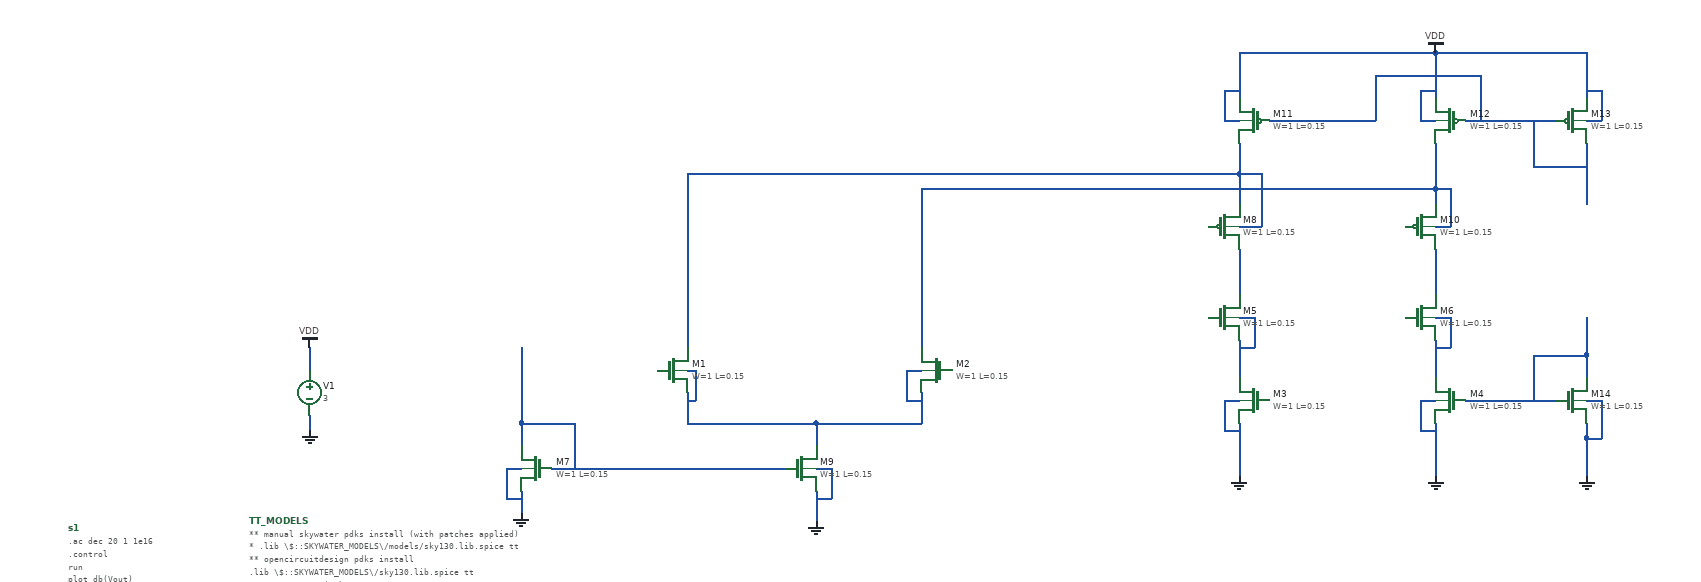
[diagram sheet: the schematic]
v {xschem version=2.9.9 file_version=1.2 }
G {}
K {}
V {}
S {}
E {}
N 1510 -730 1510 -710 { lab=GND}
N 1510 -820 1510 -790 { lab=VDD}
N 2180 -630 2180 -590 { lab=GND}
N 2010 -760 2010 -720 { lab=#net1}
N 2010 -720 2180 -720 { lab=#net1}
N 2180 -720 2180 -690 { lab=#net1}
N 2180 -720 2320 -720 { lab=#net1}
N 2320 -760 2320 -720 { lab=#net1}
N 2740 -720 2740 -650 { lab=GND}
N 3000 -720 3000 -690 { lab=GND}
N 3000 -690 3000 -650 { lab=GND}
N 2180 -660 2200 -660 { lab=GND}
N 2200 -660 2200 -620 { lab=GND}
N 2180 -620 2200 -620 { lab=GND}
N 2300 -790 2320 -790 { lab=#net1}
N 2300 -790 2300 -750 { lab=#net1}
N 2300 -750 2320 -750 { lab=#net1}
N 2010 -790 2020 -790 { lab=#net1}
N 2020 -790 2020 -750 { lab=#net1}
N 2010 -750 2020 -750 { lab=#net1}
N 2720 -750 2740 -750 { lab=GND}
N 2720 -750 2720 -710 { lab=GND}
N 2720 -710 2740 -710 { lab=GND}
N 2980 -750 3000 -750 { lab=GND}
N 2980 -750 2980 -710 { lab=GND}
N 2980 -710 3000 -710 { lab=GND}
N 2740 -830 2740 -780 { lab=#net2}
N 3000 -830 3000 -780 { lab=#net3}
N 2740 -860 2760 -860 { lab=#net2}
N 2760 -860 2760 -820 { lab=#net2}
N 2740 -820 2760 -820 { lab=#net2}
N 3000 -860 3020 -860 { lab=#net3}
N 3020 -860 3020 -820 { lab=#net3}
N 3000 -820 3020 -820 { lab=#net3}
N 2740 -980 2760 -980 { lab=#net4}
N 2740 -1090 2740 -1050 { lab=#net4}
N 3000 -980 3020 -980 { lab=#net5}
N 3020 -1030 3020 -980 { lab=#net5}
N 3000 -1030 3020 -1030 { lab=#net5}
N 3000 -1030 3000 -1010 { lab=#net5}
N 2740 -1210 2740 -1150 { lab=#net6}
N 2740 -1210 3000 -1210 { lab=#net6}
N 3000 -1210 3000 -1150 { lab=#net6}
N 2980 -1120 3000 -1120 { lab=#net6}
N 2980 -1160 2980 -1120 { lab=#net6}
N 2980 -1160 3000 -1160 { lab=#net6}
N 2720 -1120 2740 -1120 { lab=#net6}
N 2720 -1160 2720 -1120 { lab=#net6}
N 2720 -1160 2740 -1160 { lab=#net6}
N 2010 -1050 2010 -820 { lab=#net4}
N 2010 -1050 2740 -1050 { lab=#net4}
N 2760 -980 2770 -980 { lab=#net4}
N 2770 -1040 2770 -980 { lab=#net4}
N 2740 -950 2740 -890 { lab=#net7}
N 3000 -950 3000 -890 { lab=#net8}
N 2770 -1050 2770 -1040 { lab=#net4}
N 2740 -1050 2770 -1050 { lab=#net4}
N 2740 -1050 2740 -1010 { lab=#net4}
N 3000 -1090 3000 -1030 { lab=#net5}
N 2320 -1030 3000 -1030 { lab=#net5}
N 2320 -1030 2320 -820 { lab=#net5}
N 3000 -1210 3200 -1210 { lab=#net6}
N 3200 -1210 3200 -1150 { lab=#net6}
N 3200 -1120 3220 -1120 { lab=#net6}
N 3220 -1160 3220 -1120 { lab=#net6}
N 3200 -1160 3220 -1160 { lab=#net6}
N 3200 -1090 3200 -1010 { lab=#net9}
N 3040 -1120 3160 -1120 { lab=#net9}
N 2780 -1120 2920 -1120 { lab=#net9}
N 2920 -1180 2920 -1120 { lab=#net9}
N 2920 -1180 3060 -1180 { lab=#net9}
N 3060 -1180 3060 -1120 { lab=#net9}
N 3200 -750 3220 -750 { lab=GND}
N 3220 -750 3220 -700 { lab=GND}
N 3200 -700 3220 -700 { lab=GND}
N 3200 -720 3200 -700 { lab=GND}
N 3200 -700 3200 -650 { lab=GND}
N 3040 -750 3160 -750 { lab=#net10}
N 3130 -810 3130 -750 { lab=#net10}
N 3130 -810 3200 -810 { lab=#net10}
N 3200 -810 3200 -780 { lab=#net10}
N 3130 -1120 3130 -1060 { lab=#net9}
N 3130 -1060 3200 -1060 { lab=#net9}
N 3200 -860 3200 -810 { lab=#net10}
N 1790 -630 1790 -600 { lab=GND}
N 1770 -660 1790 -660 { lab=GND}
N 1770 -660 1770 -620 { lab=GND}
N 1770 -620 1790 -620 { lab=GND}
N 1830 -660 2140 -660 { lab=#net11}
N 1860 -720 1860 -660 { lab=#net11}
N 1790 -720 1860 -720 { lab=#net11}
N 1790 -720 1790 -690 { lab=#net11}
N 1790 -820 1790 -720 { lab=#net11}
C {devices/code.sym} 1430 -590 0 0 {name=TT_MODELS
only_toplevel=true
format="tcleval( @value )"
value="** manual skywater pdks install (with patches applied)
* .lib \\\\$::SKYWATER_MODELS\\\\/models/sky130.lib.spice tt

** opencircuitdesign pdks install
.lib \\\\$::SKYWATER_MODELS\\\\/sky130.lib.spice tt

.param mc_mm_switch=0
.param mc_pr_switch=0
"}
C {devices/code_shown.sym} 1190 -580 0 0 {name=s1 only_toplevel=false value=".ac dec 20 1 1e16
.control
run
plot db(Vout)
.endc
.save all"}
C {devices/vsource.sym} 1510 -760 0 0 {name=V1 value=3}
C {devices/gnd.sym} 1510 -710 0 0 {name=l1 lab=GND}
C {devices/vdd.sym} 1510 -820 0 0 {name=l11 lab=VDD}
C {sky130_fd_pr/nfet_01v8.sym} 2160 -660 0 0 {name=M9
L=0.15
W=1
nf=1 
mult=1
ad="'int((nf+1)/2) * W/nf * 0.29'" 
pd="'2*int((nf+1)/2) * (W/nf + 0.29)'"
as="'int((nf+2)/2) * W/nf * 0.29'" 
ps="'2*int((nf+2)/2) * (W/nf + 0.29)'"
nrd="'0.29 / W'" nrs="'0.29 / W'"
sa=0 sb=0 sd=0
model=nfet_01v8
spiceprefix=X
}
C {devices/gnd.sym} 2180 -590 0 0 {name=l2 lab=GND}
C {sky130_fd_pr/nfet_01v8.sym} 1990 -790 0 0 {name=M1
L=0.15
W=1
nf=1 
mult=1
ad="'int((nf+1)/2) * W/nf * 0.29'" 
pd="'2*int((nf+1)/2) * (W/nf + 0.29)'"
as="'int((nf+2)/2) * W/nf * 0.29'" 
ps="'2*int((nf+2)/2) * (W/nf + 0.29)'"
nrd="'0.29 / W'" nrs="'0.29 / W'"
sa=0 sb=0 sd=0
model=nfet_01v8
spiceprefix=X
}
C {sky130_fd_pr/nfet_01v8.sym} 2340 -790 0 1 {name=M2
L=0.15
W=1
nf=1 
mult=1
ad="'int((nf+1)/2) * W/nf * 0.29'" 
pd="'2*int((nf+1)/2) * (W/nf + 0.29)'"
as="'int((nf+2)/2) * W/nf * 0.29'" 
ps="'2*int((nf+2)/2) * (W/nf + 0.29)'"
nrd="'0.29 / W'" nrs="'0.29 / W'"
sa=0 sb=0 sd=0
model=nfet_01v8
spiceprefix=X
}
C {sky130_fd_pr/nfet_01v8.sym} 2760 -750 0 1 {name=M3
L=0.15
W=1
nf=1 
mult=1
ad="'int((nf+1)/2) * W/nf * 0.29'" 
pd="'2*int((nf+1)/2) * (W/nf + 0.29)'"
as="'int((nf+2)/2) * W/nf * 0.29'" 
ps="'2*int((nf+2)/2) * (W/nf + 0.29)'"
nrd="'0.29 / W'" nrs="'0.29 / W'"
sa=0 sb=0 sd=0
model=nfet_01v8
spiceprefix=X
}
C {sky130_fd_pr/nfet_01v8.sym} 3020 -750 0 1 {name=M4
L=0.15
W=1
nf=1 
mult=1
ad="'int((nf+1)/2) * W/nf * 0.29'" 
pd="'2*int((nf+1)/2) * (W/nf + 0.29)'"
as="'int((nf+2)/2) * W/nf * 0.29'" 
ps="'2*int((nf+2)/2) * (W/nf + 0.29)'"
nrd="'0.29 / W'" nrs="'0.29 / W'"
sa=0 sb=0 sd=0
model=nfet_01v8
spiceprefix=X
}
C {devices/gnd.sym} 2740 -650 0 0 {name=l3 lab=GND}
C {devices/gnd.sym} 3000 -650 0 0 {name=l4 lab=GND}
C {sky130_fd_pr/nfet_01v8.sym} 2720 -860 0 0 {name=M5
L=0.15
W=1
nf=1 
mult=1
ad="'int((nf+1)/2) * W/nf * 0.29'" 
pd="'2*int((nf+1)/2) * (W/nf + 0.29)'"
as="'int((nf+2)/2) * W/nf * 0.29'" 
ps="'2*int((nf+2)/2) * (W/nf + 0.29)'"
nrd="'0.29 / W'" nrs="'0.29 / W'"
sa=0 sb=0 sd=0
model=nfet_01v8
spiceprefix=X
}
C {sky130_fd_pr/nfet_01v8.sym} 2980 -860 0 0 {name=M6
L=0.15
W=1
nf=1 
mult=1
ad="'int((nf+1)/2) * W/nf * 0.29'" 
pd="'2*int((nf+1)/2) * (W/nf + 0.29)'"
as="'int((nf+2)/2) * W/nf * 0.29'" 
ps="'2*int((nf+2)/2) * (W/nf + 0.29)'"
nrd="'0.29 / W'" nrs="'0.29 / W'"
sa=0 sb=0 sd=0
model=nfet_01v8
spiceprefix=X
}
C {sky130_fd_pr/pfet_01v8.sym} 2720 -980 0 0 {name=M8
L=0.15
W=1
nf=1
mult=1
ad="'int((nf+1)/2) * W/nf * 0.29'" 
pd="'2*int((nf+1)/2) * (W/nf + 0.29)'"
as="'int((nf+2)/2) * W/nf * 0.29'" 
ps="'2*int((nf+2)/2) * (W/nf + 0.29)'"
nrd="'0.29 / W'" nrs="'0.29 / W'"
sa=0 sb=0 sd=0
model=pfet_01v8
spiceprefix=X
}
C {sky130_fd_pr/pfet_01v8.sym} 2980 -980 0 0 {name=M10
L=0.15
W=1
nf=1
mult=1
ad="'int((nf+1)/2) * W/nf * 0.29'" 
pd="'2*int((nf+1)/2) * (W/nf + 0.29)'"
as="'int((nf+2)/2) * W/nf * 0.29'" 
ps="'2*int((nf+2)/2) * (W/nf + 0.29)'"
nrd="'0.29 / W'" nrs="'0.29 / W'"
sa=0 sb=0 sd=0
model=pfet_01v8
spiceprefix=X
}
C {sky130_fd_pr/pfet_01v8.sym} 2760 -1120 0 1 {name=M11
L=0.15
W=1
nf=1
mult=1
ad="'int((nf+1)/2) * W/nf * 0.29'" 
pd="'2*int((nf+1)/2) * (W/nf + 0.29)'"
as="'int((nf+2)/2) * W/nf * 0.29'" 
ps="'2*int((nf+2)/2) * (W/nf + 0.29)'"
nrd="'0.29 / W'" nrs="'0.29 / W'"
sa=0 sb=0 sd=0
model=pfet_01v8
spiceprefix=X
}
C {sky130_fd_pr/pfet_01v8.sym} 3020 -1120 0 1 {name=M12
L=0.15
W=1
nf=1
mult=1
ad="'int((nf+1)/2) * W/nf * 0.29'" 
pd="'2*int((nf+1)/2) * (W/nf + 0.29)'"
as="'int((nf+2)/2) * W/nf * 0.29'" 
ps="'2*int((nf+2)/2) * (W/nf + 0.29)'"
nrd="'0.29 / W'" nrs="'0.29 / W'"
sa=0 sb=0 sd=0
model=pfet_01v8
spiceprefix=X
}
C {sky130_fd_pr/pfet_01v8.sym} 3180 -1120 0 0 {name=M13
L=0.15
W=1
nf=1
mult=1
ad="'int((nf+1)/2) * W/nf * 0.29'" 
pd="'2*int((nf+1)/2) * (W/nf + 0.29)'"
as="'int((nf+2)/2) * W/nf * 0.29'" 
ps="'2*int((nf+2)/2) * (W/nf + 0.29)'"
nrd="'0.29 / W'" nrs="'0.29 / W'"
sa=0 sb=0 sd=0
model=pfet_01v8
spiceprefix=X
}
C {sky130_fd_pr/nfet_01v8.sym} 3180 -750 0 0 {name=M14
L=0.15
W=1
nf=1 
mult=1
ad="'int((nf+1)/2) * W/nf * 0.29'" 
pd="'2*int((nf+1)/2) * (W/nf + 0.29)'"
as="'int((nf+2)/2) * W/nf * 0.29'" 
ps="'2*int((nf+2)/2) * (W/nf + 0.29)'"
nrd="'0.29 / W'" nrs="'0.29 / W'"
sa=0 sb=0 sd=0
model=nfet_01v8
spiceprefix=X
}
C {devices/gnd.sym} 3200 -650 0 0 {name=l5 lab=GND}
C {sky130_fd_pr/nfet_01v8.sym} 1810 -660 0 1 {name=M7
L=0.15
W=1
nf=1 
mult=1
ad="'int((nf+1)/2) * W/nf * 0.29'" 
pd="'2*int((nf+1)/2) * (W/nf + 0.29)'"
as="'int((nf+2)/2) * W/nf * 0.29'" 
ps="'2*int((nf+2)/2) * (W/nf + 0.29)'"
nrd="'0.29 / W'" nrs="'0.29 / W'"
sa=0 sb=0 sd=0
model=nfet_01v8
spiceprefix=X
}
C {devices/gnd.sym} 1790 -600 0 0 {name=l6 lab=GND}
C {devices/vdd.sym} 3000 -1210 0 0 {name=l7 lab=VDD}
